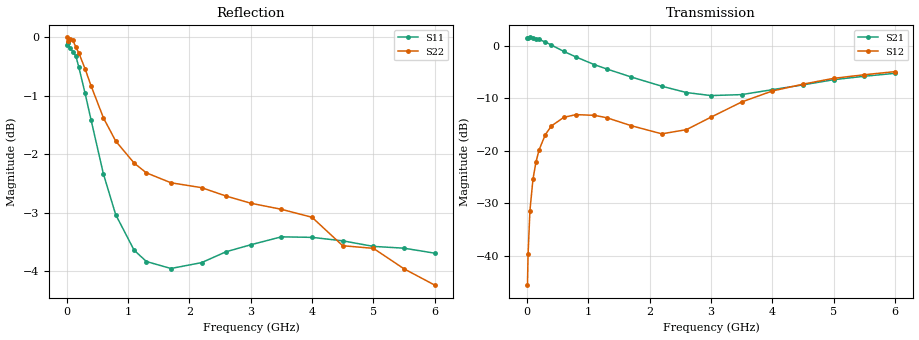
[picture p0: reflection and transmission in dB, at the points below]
! Infineon Technologies  Discrete & RF Semiconductors
! BFS17W
! Si NPN RF Bipolar Junction Transistor in SOT323
! VCE = 1.5 V  IC = 0.3 mA
! Common Emitter S-Parameters:  August  1999
# GHz  S  MA  R  50
!  f  S11  S21  S12  S22
! GHz  MAG  ANG  MAG  ANG  MAG  ANG  MAG  ANG
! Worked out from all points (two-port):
!   36 points, 10 MHz to 6 GHz, reference 50 ohm
!   highest |S21| = 1.55 dB at 50 MHz (marker M1); lowest = -9.5 dB at 3 GHz (marker M2)
!   |S21| within 3 dB of the highest: start of sweep to 662.8 MHz
!   lowest |S11| = -3.9 dB at 1.7 GHz (marker M3), VSWR 4.47, Z = 11.2 - j2.16 ohm
!   |S11| at or under -10 dB: nowhere
!   |S22| runs from -4.2 to 0.0 dB; largest |S21 - S12| = 1.2
!   S11 on the Smith chart (normalised r, x): 10 MHz: 28, -53; 300 MHz: 0.27, -1.98; 600 MHz: 0.25, -0.90; 1.3 GHz: 0.23, -0.22; 3 GHz: 0.23, +0.39; 6 GHz: 0.49, +1.09
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0.01  0.9845 -1.7  1.192 179.2  0.0053 87.8  0.9999 -0.1
0.02  0.9881 -3.9  1.192 176.9  0.0104 87.3  0.9923 -1.1
0.05  0.9798 -9.2  1.196 171.8  0.027 84.0  0.9972 -3.1
0.1  0.9725 -18.1  1.178 164.1  0.0541 78.1  0.9942 -6.1
0.15  0.9638 -28.0  1.166 155.6  0.079 71.8  0.9811 -9.0
0.2  0.9426 -36.2  1.142 148.0  0.1024 67.3  0.9692 -11.8
0.3  0.8961 -52.9  1.081 133.4  0.142 57.1  0.9402 -16.8
0.4  0.8493 -68.0  1.012 119.9  0.1722 48.2  0.9085 -21.3
0.6  0.7642 -94.0  0.881 97.9  0.2078 34.4  0.8535 -28.4
0.8  0.7055 -114.9  0.78 80.6  0.2208 24.6  0.8154 -34.9
1.1  0.6579 -139.9  0.659 60.7  0.2174 14.8  0.7809 -44.0
1.3  0.6434 -153.4  0.6 50.8  0.2065 10.9  0.766 -50.4
1.7  0.6346 -174.8  0.503 36.0  0.1734 9.9  0.7512 -63.5
2.2  0.642 163.5  0.411 26.0  0.145 25.2  0.744 -80.5
2.6  0.6559 148.7  0.358 24.3  0.1589 44.1  0.7318 -94.6
3  0.6649 135.5  0.335 27.4  0.2086 54.4  0.7216 -108.0
3.5  0.6754 121.0  0.342 32.6  0.2909 55.6  0.713 -125.1
4  0.6747 109.0  0.381 34.8  0.3701 50.4  0.7019 -142.6
4.5  0.6701 98.7  0.423 33.5  0.4298 43.7  0.6637 -158.2
5  0.6628 91.0  0.474 30.2  0.4883 37.3  0.6603 -171.0
5.5  0.6605 84.2  0.511 26.1  0.5284 30.9  0.6342 175.7
6  0.654 78.9  0.545 21.6  0.5651 25.1  0.6142 164.2
